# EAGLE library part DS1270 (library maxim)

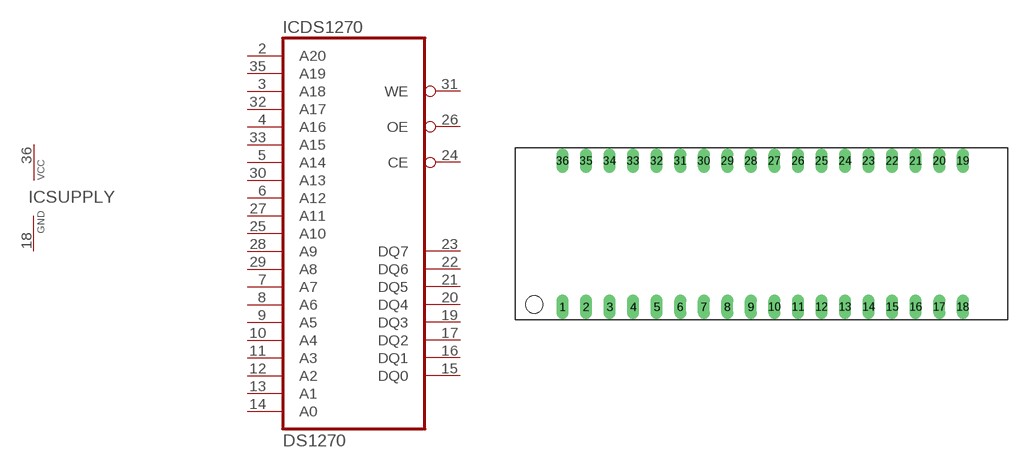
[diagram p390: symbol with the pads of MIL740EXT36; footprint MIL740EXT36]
Designator prefix IC; gates DS1270=DS12__ SUPPLY=VCC-GND

## DS1270  [MIL740EXT36]
2  DS1270:A20  in
3  DS1270:A18  in
4  DS1270:A16  in
5  DS1270:A14  in
6  DS1270:A12  in
7  DS1270:A7  in
8  DS1270:A6  in
9  DS1270:A5  in
10  DS1270:A4  in
11  DS1270:A3  in
12  DS1270:A2  in
13  DS1270:A1  in
14  DS1270:A0  in
15  DS1270:DQ0
16  DS1270:DQ1
17  DS1270:DQ2
18  SUPPLY:GND  pwr
19  DS1270:DQ3
20  DS1270:DQ4
21  DS1270:DQ5
22  DS1270:DQ6
23  DS1270:DQ7
24  DS1270:CE  in
25  DS1270:A10  in
26  DS1270:OE  in
27  DS1270:A11  in
28  DS1270:A9  in
29  DS1270:A8  in
30  DS1270:A13  in
31  DS1270:WE  in
32  DS1270:A17  in
33  DS1270:A15  in
35  DS1270:A19  in
36  SUPPLY:VCC  pwr

## Footprint MIL740EXT36 (pad centres in mm)
drill 0.813 long: 1 -20.32,-7.112; 2 -17.78,-7.112; 3 -15.24,-7.112; 4 -12.7,-7.112; 5 -10.16,-7.112; 6 -7.62,-7.112; 7 -5.08,-7.112; 8 -2.54,-7.112; 9 0,-7.112; 10 2.54,-7.112; 11 5.08,-7.112; 12 7.62,-7.112; 13 10.16,-7.112; 14 12.7,-7.112; 15 15.24,-7.112; 16 17.78,-7.112; 17 20.32,-7.112; 18 22.86,-7.112; 19 22.86,8.636; 20 20.32,8.636; 21 17.78,8.636; 22 15.24,8.636; 23 12.7,8.636; 24 10.16,8.636; 25 7.62,8.636; 26 5.08,8.636; 27 2.54,8.636; 28 0,8.636; 29 -2.54,8.636; 30 -5.08,8.636; 31 -7.62,8.636; 32 -10.16,8.636; 33 -12.7,8.636; 34 -15.24,8.636; 35 -17.78,8.636; 36 -20.32,8.636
